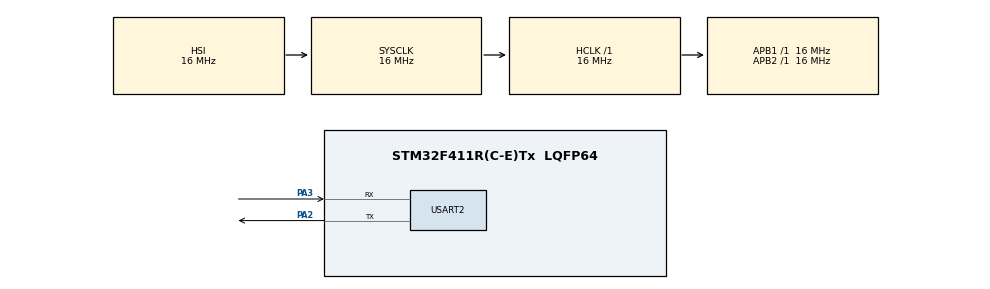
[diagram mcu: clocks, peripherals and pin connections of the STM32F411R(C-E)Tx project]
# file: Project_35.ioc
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FREERTOS.Tasks01=defaultTask,0,128,StartDefaultTask,Default,NULL,Dynamic,NULL,NULL
FREERTOS.configUSE_TIMERS=1
Mcu.Family=STM32F4
Mcu.Name=STM32F411R(C-E)Tx
Mcu.Package=LQFP64
NVIC.PriorityGroup=NVIC_PRIORITYGROUP_4
PA2.Mode=Asynchronous
PA2.Signal=USART2_TX
PA3.Mode=Asynchronous
PA3.Signal=USART2_RX
ProjectManager.HeapSize=0x200
ProjectManager.StackSize=0x400
ProjectManager.TargetToolchain=MDK-ARM V5.27
RCC.AHBFreq_Value=16000000
RCC.APB1Freq_Value=16000000
RCC.APB2Freq_Value=16000000
RCC.CortexFreq_Value=16000000
RCC.HSE_VALUE=25000000
RCC.HSI_VALUE=16000000
RCC.LSE_VALUE=32768
RCC.SYSCLKFreq_VALUE=16000000
RCC.VCOOutputFreq_Value=192000000
TIM4.Period=84
USART2.VirtualMode=VM_ASYNC
VP_FREERTOS_VS_CMSIS_V1.Mode=CMSIS_V1
VP_TIM4_VS_ClockSourceINT.Mode=Internal
board=custom

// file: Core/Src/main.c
/* USER CODE BEGIN Header */
/**
  ******************************************************************************
  * @file           : main.c
  * @brief          : Main program body
  ******************************************************************************
  * @attention
  *
  * <h2><center>&copy; Copyright (c) 2021 STMicroelectronics.
  * All rights reserved.</center></h2>
  *
  * This software component is licensed by ST under Ultimate Liberty license
  * SLA0044, the "License"; You may not use this file except in compliance with
  * the License. You may obtain a copy of the License at:
  *                             www.st.com/SLA0044
  *
  ******************************************************************************
  */
/* USER CODE END Header */
#include "main.h"
#include "cmsis_os.h"
/* USER CODE BEGIN Includes */
#include <string.h>
#include <stdio.h>

/* USER CODE END Includes */

/* USER CODE BEGIN PD */
#define usTIM	TIM4
/* USER CODE END PD */

/* USER CODE BEGIN PM */
#define TRIG_GPIO_Port GPIOC
#define TRIG_Pin GPIO_PIN_8
#define ECHO_GPIO_Port GPIOC
#define ECHO_Pin GPIO_PIN_6
/* USER CODE END PM */

TIM_HandleTypeDef htim4;
UART_HandleTypeDef huart2;
QueueHandle_t queue;

void SystemClock_Config(void);
static void MX_GPIO_Init(void);
static void MX_TIM4_Init(void);
static void MX_USART2_UART_Init(void);
static void usDelay(uint32_t);
void task1(void*);
void task2(void*);

/* USER CODE BEGIN 0 */
const float speedOfSound = 0.0343/2;
char uartBuf[100];

/* USER CODE END 0 */

int main(void)
{

  /* MCU Configuration--------------------------------------------------------*/

  /* Reset of all peripherals, Initializes the Flash interface and the Systick. */
  HAL_Init();

  /* Configure the system clock */
  SystemClock_Config();

  /* Initialize all configured peripherals */
  MX_GPIO_Init();
  MX_TIM4_Init();
  MX_USART2_UART_Init();

  /* USER CODE BEGIN RTOS_QUEUES */
  queue = xQueueCreate(1, sizeof(float));
  /* USER CODE END RTOS_QUEUES */

  /* Create the thread(s) */
  /* definition and creation of defaultTask */

  /* USER CODE BEGIN RTOS_THREADS */
    xTaskCreate(task1, "Task1", configMINIMAL_STACK_SIZE, NULL, 7, NULL);
		xTaskCreate(task2, "Task2", configMINIMAL_STACK_SIZE, NULL, 7, NULL);
  /* USER CODE END RTOS_THREADS */

  /* Start scheduler */
	vTaskStartScheduler();

  /* We should never get here as control is now taken by the scheduler */
  /* Infinite loop */
  while (1)
  {

  }
}

void SystemClock_Config(void)
{
  RCC_OscInitTypeDef RCC_OscInitStruct = {0};
  RCC_ClkInitTypeDef RCC_ClkInitStruct = {0};

  /** Configure the main internal regulator output voltage
  */
  __HAL_RCC_PWR_CLK_ENABLE();
  __HAL_PWR_VOLTAGESCALING_CONFIG(PWR_REGULATOR_VOLTAGE_SCALE1);
  /** Initializes the RCC Oscillators according to the specified parameters
  * in the RCC_OscInitTypeDef structure.
  */
  RCC_OscInitStruct.OscillatorType = RCC_OSCILLATORTYPE_HSI;
  RCC_OscInitStruct.HSIState = RCC_HSI_ON;
  RCC_OscInitStruct.HSICalibrationValue = RCC_HSICALIBRATION_DEFAULT;
  RCC_OscInitStruct.PLL.PLLState = RCC_PLL_NONE;
  if (HAL_RCC_OscConfig(&RCC_OscInitStruct) != HAL_OK)
  {
    Error_Handler();
  }
  /** Initializes the CPU, AHB and APB buses clocks
  */
  RCC_ClkInitStruct.ClockType = RCC_CLOCKTYPE_HCLK|RCC_CLOCKTYPE_SYSCLK
                              |RCC_CLOCKTYPE_PCLK1|RCC_CLOCKTYPE_PCLK2;
  RCC_ClkInitStruct.SYSCLKSource = RCC_SYSCLKSOURCE_HSI;
  RCC_ClkInitStruct.AHBCLKDivider = RCC_SYSCLK_DIV1;
  RCC_ClkInitStruct.APB1CLKDivider = RCC_HCLK_DIV1;
  RCC_ClkInitStruct.APB2CLKDivider = RCC_HCLK_DIV1;

  if (HAL_RCC_ClockConfig(&RCC_ClkInitStruct, FLASH_LATENCY_0) != HAL_OK)
  {
    Error_Handler();
  }
}

static void MX_TIM4_Init(void)
{

  TIM_ClockConfigTypeDef sClockSourceConfig = {0};
  TIM_MasterConfigTypeDef sMasterConfig = {0};

  htim4.Instance = TIM4;
  htim4.Init.Prescaler = 84-1;
  htim4.Init.CounterMode = TIM_COUNTERMODE_UP;
  htim4.Init.Period = 0;
  htim4.Init.ClockDivision = TIM_CLOCKDIVISION_DIV1;
  htim4.Init.AutoReloadPreload = TIM_AUTORELOAD_PRELOAD_DISABLE;
  if (HAL_TIM_Base_Init(&htim4) != HAL_OK)
  {
    Error_Handler();
  }
  sClockSourceConfig.ClockSource = TIM_CLOCKSOURCE_INTERNAL;
  if (HAL_TIM_ConfigClockSource(&htim4, &sClockSourceConfig) != HAL_OK)
  {
    Error_Handler();
  }
  sMasterConfig.MasterOutputTrigger = TIM_TRGO_RESET;
  sMasterConfig.MasterSlaveMode = TIM_MASTERSLAVEMODE_DISABLE;
  if (HAL_TIMEx_MasterConfigSynchronization(&htim4, &sMasterConfig) != HAL_OK)
  {
    Error_Handler();
  }

}

static void MX_USART2_UART_Init(void)
{

  huart2.Instance = USART2;
  huart2.Init.BaudRate = 115200;
  huart2.Init.WordLength = UART_WORDLENGTH_8B;
  huart2.Init.StopBits = UART_STOPBITS_1;
  huart2.Init.Parity = UART_PARITY_NONE;
  huart2.Init.Mode = UART_MODE_TX_RX;
  huart2.Init.HwFlowCtl = UART_HWCONTROL_NONE;
  huart2.Init.OverSampling = UART_OVERSAMPLING_16;
  if (HAL_UART_Init(&huart2) != HAL_OK)
  {
    Error_Handler();
  }

}

static void MX_GPIO_Init(void)
{

	GPIO_InitTypeDef GPIO_InitStruct = {0};

  /* GPIO Ports Clock Enable */
  __HAL_RCC_GPIOA_CLK_ENABLE();
	__HAL_RCC_GPIOC_CLK_ENABLE();

	GPIO_InitStruct.Pin = TRIG_Pin;
  GPIO_InitStruct.Mode = GPIO_MODE_OUTPUT_PP;
  GPIO_InitStruct.Pull = GPIO_NOPULL;
  GPIO_InitStruct.Speed = GPIO_SPEED_FREQ_LOW;
  HAL_GPIO_Init(TRIG_GPIO_Port, &GPIO_InitStruct);

	GPIO_InitStruct.Pin = ECHO_Pin;
  GPIO_InitStruct.Mode = GPIO_MODE_INPUT;
  GPIO_InitStruct.Pull = GPIO_NOPULL;
  GPIO_InitStruct.Speed = GPIO_SPEED_FREQ_LOW;
  HAL_GPIO_Init(ECHO_GPIO_Port, &GPIO_InitStruct);

}

/* USER CODE BEGIN 4 */

void usDelay(uint32_t uSec){
	if(uSec < 2) uSec = 2;
	usTIM->ARR = uSec - 1; 	/*sets the value in the auto-reload register*/
	usTIM->EGR = 1; 			/*Re-initialises the timer*/
	usTIM->SR &= ~1; 		//Resets the flag
	usTIM->CR1 |= 1; 		//Enables the counter
	while((usTIM->SR&0x0001) != 1);
	usTIM->SR &= ~(0x0001);
}

void task1(void *param){

	float distance = 0;
	uint32_t numTicks = 0;

	while (1){
    /* USER CODE END WHILE */

    /* USER CODE BEGIN 3 */
		//Set TRIG to LOW for few uSec
		HAL_GPIO_WritePin(TRIG_GPIO_Port, TRIG_Pin, GPIO_PIN_RESET);
		usDelay(3);

		//*** START Ultrasonic measure routine ***//
		//1. Output 10 usec TRIG
		HAL_GPIO_WritePin(TRIG_GPIO_Port, TRIG_Pin, GPIO_PIN_SET);
		usDelay(10);
		HAL_GPIO_WritePin(TRIG_GPIO_Port, TRIG_Pin, GPIO_PIN_RESET);

		//2. Wait for ECHO pin rising edge
		while(HAL_GPIO_ReadPin(ECHO_GPIO_Port, ECHO_Pin) == GPIO_PIN_RESET);

		//3. Start measuring ECHO pulse width in usec
		numTicks = 0;
		while(HAL_GPIO_ReadPin(ECHO_GPIO_Port, ECHO_Pin) == GPIO_PIN_SET)
		{
			numTicks++;
			usDelay(2); //2.8usec
		};

		//4. Estimate distance in cm
		distance = (numTicks + 0.0f)*2.8*speedOfSound;

		//5. Print to UART terminal for debugging
		sprintf(uartBuf, "Distance (cm)  = %.1f\r\n", distance);
		HAL_UART_Transmit(&huart2, (uint8_t *)uartBuf, strlen(uartBuf), 100);
		xQueueSend(queue, &distance, HAL_MAX_DELAY);
		// wait 1s
		vTaskDelay( pdMS_TO_TICKS(1000) );
  }
}

#define Buzzer_GPIO_PIN 5
#define Buzzer_GPIO_PORT GPIOA

void buzzer_sound(int time_ms){

	HAL_GPIO_WritePin(Buzzer_GPIO_PORT, Buzzer_GPIO_PIN, GPIO_PIN_SET);
	vTaskDelay(time_ms);
	HAL_GPIO_WritePin(Buzzer_GPIO_PORT, Buzzer_GPIO_PIN, GPIO_PIN_RESET);
	vTaskDelay(time_ms);

}

void task2(void *param){

	// distance in cm
	float distance = 0;

	while(1){

		// receive param via queue
		xQueueReceive(queue, &distance, HAL_MAX_DELAY);
		if(distance < 100){
			buzzer_sound(50);
		}else if(distance < 150){
			buzzer_sound(150);
		}else{
			buzzer_sound(250);
		}

	}

}

/* USER CODE END 4 */

/* USER CODE BEGIN Header_StartDefaultTask */

void Error_Handler(void)
{
  __disable_irq();
  while (1)
  {
  }
}

/************************ (C) COPYRIGHT STMicroelectronics *****END OF FILE****/

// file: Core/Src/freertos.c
/* USER CODE BEGIN Header */
/**
  ******************************************************************************
  * File Name          : freertos.c
  * Description        : Code for freertos applications
  ******************************************************************************
  * @attention
  *
  * <h2><center>&copy; Copyright (c) 2021 STMicroelectronics.
  * All rights reserved.</center></h2>
  *
  * This software component is licensed by ST under Ultimate Liberty license
  * SLA0044, the "License"; You may not use this file except in compliance with
  * the License. You may obtain a copy of the License at:
  *                             www.st.com/SLA0044
  *
  ******************************************************************************
  */
/* USER CODE END Header */

#include "FreeRTOS.h"
#include "task.h"
#include "main.h"

/* GetIdleTaskMemory prototype (linked to static allocation support) */
void vApplicationGetIdleTaskMemory( StaticTask_t **ppxIdleTaskTCBBuffer, StackType_t **ppxIdleTaskStackBuffer, uint32_t *pulIdleTaskStackSize );

/* GetTimerTaskMemory prototype (linked to static allocation support) */
void vApplicationGetTimerTaskMemory( StaticTask_t **ppxTimerTaskTCBBuffer, StackType_t **ppxTimerTaskStackBuffer, uint32_t *pulTimerTaskStackSize );

/* USER CODE BEGIN GET_IDLE_TASK_MEMORY */
static StaticTask_t xIdleTaskTCBBuffer;
static StackType_t xIdleStack[configMINIMAL_STACK_SIZE];

void vApplicationGetIdleTaskMemory( StaticTask_t **ppxIdleTaskTCBBuffer, StackType_t **ppxIdleTaskStackBuffer, uint32_t *pulIdleTaskStackSize )
{
  *ppxIdleTaskTCBBuffer = &xIdleTaskTCBBuffer;
  *ppxIdleTaskStackBuffer = &xIdleStack[0];
  *pulIdleTaskStackSize = configMINIMAL_STACK_SIZE;
  /* place for user code */
}
/* USER CODE END GET_IDLE_TASK_MEMORY */

/* USER CODE BEGIN GET_TIMER_TASK_MEMORY */
static StaticTask_t xTimerTaskTCBBuffer;
static StackType_t xTimerStack[configTIMER_TASK_STACK_DEPTH];

void vApplicationGetTimerTaskMemory( StaticTask_t **ppxTimerTaskTCBBuffer, StackType_t **ppxTimerTaskStackBuffer, uint32_t *pulTimerTaskStackSize )
{
  *ppxTimerTaskTCBBuffer = &xTimerTaskTCBBuffer;
  *ppxTimerTaskStackBuffer = &xTimerStack[0];
  *pulTimerTaskStackSize = configTIMER_TASK_STACK_DEPTH;
  /* place for user code */
}
/* USER CODE END GET_TIMER_TASK_MEMORY */

/************************ (C) COPYRIGHT STMicroelectronics *****END OF FILE****/
